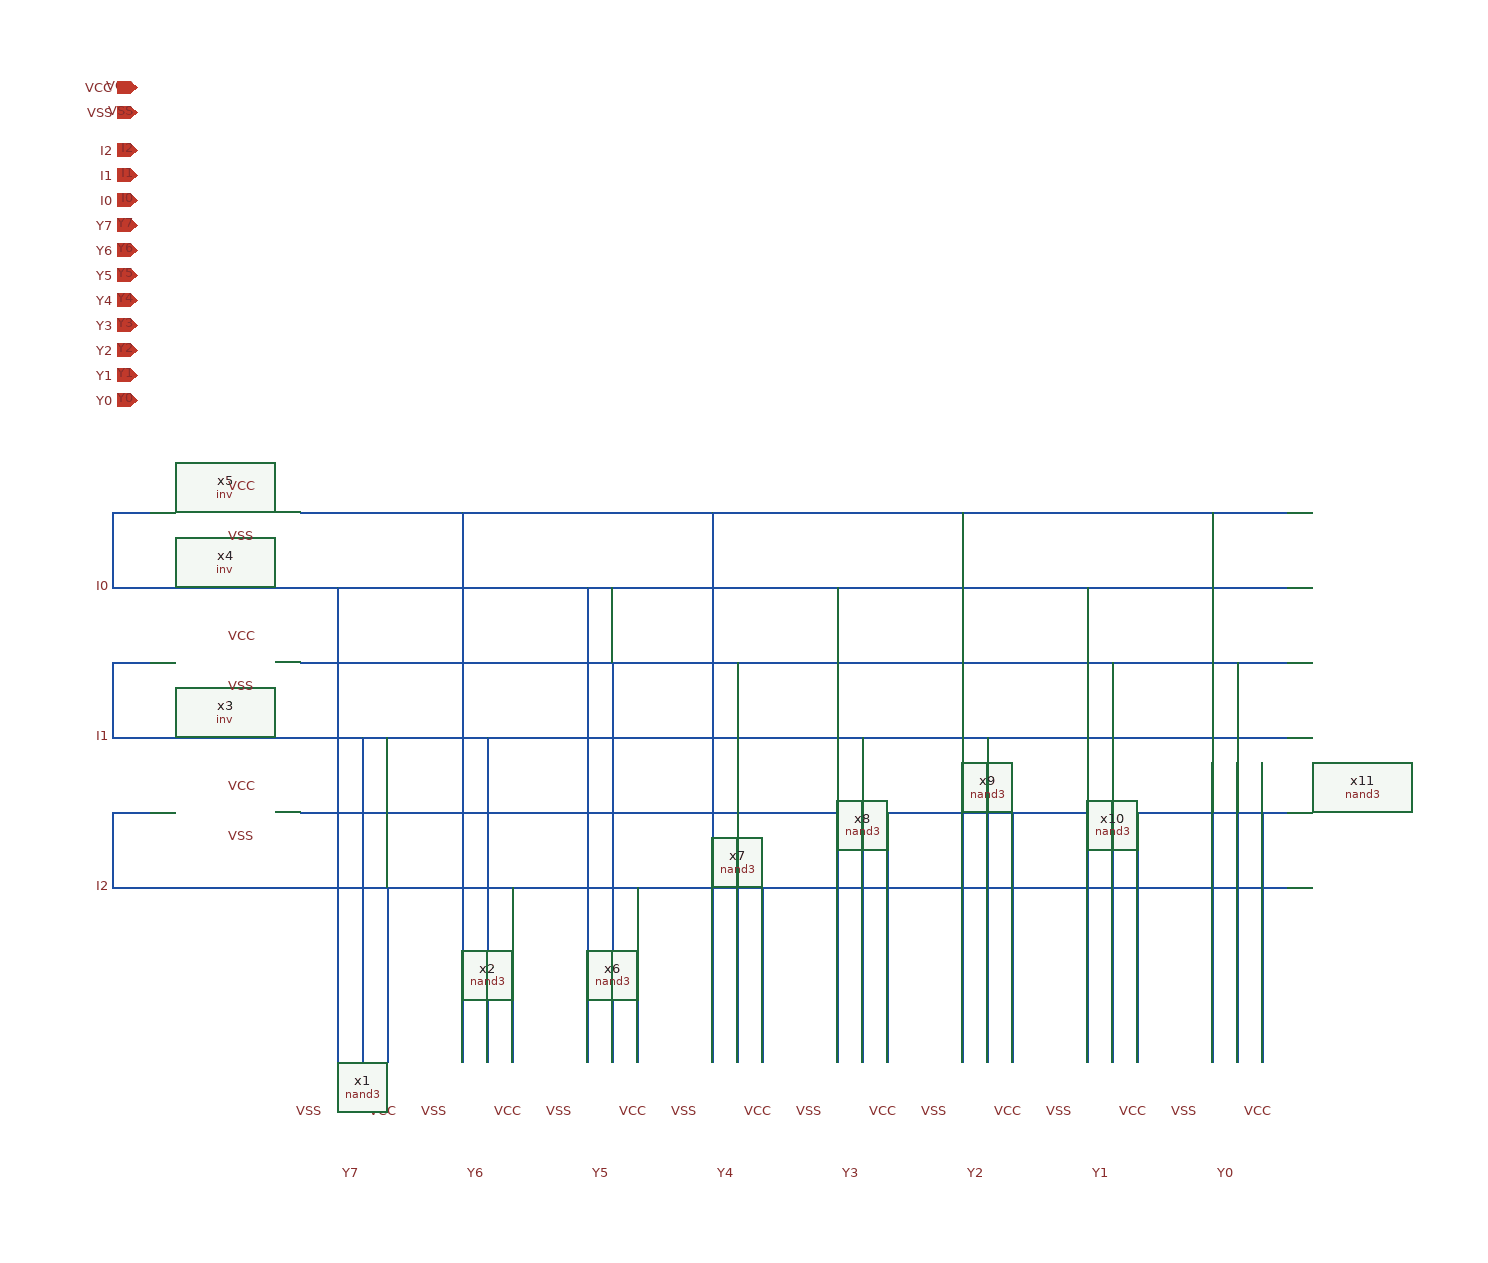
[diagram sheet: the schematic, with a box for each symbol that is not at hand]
v {xschem version=3.4.8RC file_version=1.3}
G {}
K {}
V {}
S {}
F {}
E {}
N 40 -240 40 -180 {lab=I0}
N 40 -240 70 -240 {lab=I0}
N 40 -120 40 -60 {lab=I1}
N 40 -120 70 -120 {lab=I1}
N 40 0 40 60 {lab=I2}
N 40 0 70 0 {lab=I2}
N 40 -180 980 -180 {lab=I0}
N 190 -240 980 -240 {lab=#net1}
N 40 -60 980 -60 {lab=I1}
N 190 -120 980 -120 {lab=#net2}
N 40 60 980 60 {lab=I2}
N 190 0 980 0 {lab=#net3}
N 220 -180 220 200 {lab=I0}
N 240 -60 240 200 {lab=I1}
N 260 60 260 200 {lab=I2}
N 360 60 360 200 {lab=I2}
N 460 60 460 200 {lab=I2}
N 560 60 560 200 {lab=I2}
N 660 0 660 200 {lab=#net3}
N 760 0 760 200 {lab=#net3}
N 860 0 860 200 {lab=#net3}
N 960 0 960 200 {lab=#net3}
N 320 -240 320 200 {lab=#net1}
N 520 -240 520 200 {lab=#net1}
N 720 -240 720 200 {lab=#net1}
N 920 -240 920 200 {lab=#net1}
N 420 -180 420 200 {lab=I0}
N 620 -180 620 200 {lab=I0}
N 820 -180 820 200 {lab=I0}
N 340 -60 340 200 {lab=I1}
N 440 -120 440 200 {lab=#net2}
N 540 -120 540 200 {lab=#net2}
N 640 -60 640 200 {lab=I1}
N 740 -60 740 200 {lab=I1}
N 840 -120 840 200 {lab=#net2}
N 940 -120 940 200 {lab=#net2}
C {iopin.sym} 60 -530 0 0 {name=p1 lab=I2}
C {iopin.sym} 60 -510 0 0 {name=p2 lab=I1}
C {iopin.sym} 60 -490 0 0 {name=p3 lab=I0}
C {iopin.sym} 60 -470 0 0 {name=p4 lab=Y7}
C {iopin.sym} 60 -450 0 0 {name=p5 lab=Y6}
C {iopin.sym} 60 -430 0 0 {name=p6 lab=Y5}
C {iopin.sym} 60 -410 0 0 {name=p7 lab=Y4}
C {iopin.sym} 60 -390 0 0 {name=p8 lab=Y3}
C {iopin.sym} 60 -370 0 0 {name=p9 lab=Y2}
C {iopin.sym} 60 -350 0 0 {name=p10 lab=Y1}
C {iopin.sym} 60 -330 0 0 {name=p11 lab=Y0}
C {inv.sym} 130 0 0 0 {name=x3}
C {lab_pin.sym} 60 -530 0 0 {name=p13 sig_type=std_logic lab=I2}
C {lab_pin.sym} 60 -510 0 0 {name=p14 sig_type=std_logic lab=I1}
C {lab_pin.sym} 60 -490 0 0 {name=p15 sig_type=std_logic lab=I0}
C {lab_pin.sym} 60 -470 0 0 {name=p12 sig_type=std_logic lab=Y7}
C {lab_pin.sym} 60 -450 0 0 {name=p16 sig_type=std_logic lab=Y6}
C {lab_pin.sym} 60 -430 0 0 {name=p17 sig_type=std_logic lab=Y5}
C {lab_pin.sym} 60 -410 0 0 {name=p18 sig_type=std_logic lab=Y4}
C {lab_pin.sym} 60 -390 0 0 {name=p19 sig_type=std_logic lab=Y3}
C {lab_pin.sym} 60 -370 0 0 {name=p20 sig_type=std_logic lab=Y2}
C {lab_pin.sym} 60 -350 0 0 {name=p21 sig_type=std_logic lab=Y1}
C {lab_pin.sym} 60 -330 0 0 {name=p22 sig_type=std_logic lab=Y0}
C {lab_pin.sym} 40 60 2 1 {name=p23 sig_type=std_logic lab=I2}
C {lab_pin.sym} 40 -60 2 1 {name=p24 sig_type=std_logic lab=I1}
C {lab_pin.sym} 40 -180 2 1 {name=p25 sig_type=std_logic lab=I0}
C {inv.sym} 130 -120 0 0 {name=x4}
C {inv.sym} 130 -240 0 0 {name=x5}
C {lab_pin.sym} 240 290 0 0 {name=p26 sig_type=std_logic lab=Y7}
C {lab_pin.sym} 340 290 0 0 {name=p27 sig_type=std_logic lab=Y6}
C {lab_pin.sym} 440 290 0 0 {name=p28 sig_type=std_logic lab=Y5}
C {lab_pin.sym} 540 290 0 0 {name=p29 sig_type=std_logic lab=Y4}
C {lab_pin.sym} 640 290 0 0 {name=p30 sig_type=std_logic lab=Y3}
C {lab_pin.sym} 740 290 0 0 {name=p31 sig_type=std_logic lab=Y2}
C {lab_pin.sym} 840 290 0 0 {name=p32 sig_type=std_logic lab=Y1}
C {lab_pin.sym} 940 290 0 0 {name=p33 sig_type=std_logic lab=Y0}
C {lab_pin.sym} 60 -580 0 0 {name=p34 sig_type=std_logic lab=VCC}
C {iopin.sym} 60 -580 0 0 {name=p35 lab=VCC}
C {iopin.sym} 60 -560 0 0 {name=p36 lab=VSS}
C {lab_pin.sym} 60 -560 0 0 {name=p37 sig_type=std_logic lab=VSS}
C {lab_pin.sym} 130 -260 0 1 {name=p38 sig_type=std_logic lab=VCC}
C {lab_pin.sym} 130 -220 0 1 {name=p39 sig_type=std_logic lab=VSS}
C {lab_pin.sym} 130 -140 0 1 {name=p40 sig_type=std_logic lab=VCC}
C {lab_pin.sym} 130 -100 0 1 {name=p41 sig_type=std_logic lab=VSS}
C {lab_pin.sym} 130 -20 0 1 {name=p42 sig_type=std_logic lab=VCC}
C {lab_pin.sym} 130 20 0 1 {name=p43 sig_type=std_logic lab=VSS}
C {lab_pin.sym} 970 240 1 0 {name=p44 sig_type=std_logic lab=VCC}
C {lab_pin.sym} 910 240 1 0 {name=p45 sig_type=std_logic lab=VSS}
C {lab_pin.sym} 870 240 1 0 {name=p46 sig_type=std_logic lab=VCC}
C {lab_pin.sym} 810 240 1 0 {name=p47 sig_type=std_logic lab=VSS}
C {lab_pin.sym} 770 240 1 0 {name=p48 sig_type=std_logic lab=VCC}
C {lab_pin.sym} 710 240 1 0 {name=p49 sig_type=std_logic lab=VSS}
C {lab_pin.sym} 670 240 1 0 {name=p50 sig_type=std_logic lab=VCC}
C {lab_pin.sym} 610 240 1 0 {name=p51 sig_type=std_logic lab=VSS}
C {lab_pin.sym} 570 240 1 0 {name=p52 sig_type=std_logic lab=VCC}
C {lab_pin.sym} 510 240 1 0 {name=p53 sig_type=std_logic lab=VSS}
C {lab_pin.sym} 470 240 1 0 {name=p54 sig_type=std_logic lab=VCC}
C {lab_pin.sym} 410 240 1 0 {name=p55 sig_type=std_logic lab=VSS}
C {lab_pin.sym} 370 240 1 0 {name=p56 sig_type=std_logic lab=VCC}
C {lab_pin.sym} 310 240 1 0 {name=p57 sig_type=std_logic lab=VSS}
C {lab_pin.sym} 270 240 1 0 {name=p58 sig_type=std_logic lab=VCC}
C {lab_pin.sym} 210 240 1 0 {name=p59 sig_type=std_logic lab=VSS}
C {logic gates/nand3.sym} 240 240 1 0 {name=x1}
C {logic gates/nand3.sym} 340 240 1 0 {name=x2}
C {logic gates/nand3.sym} 440 240 1 0 {name=x6}
C {logic gates/nand3.sym} 540 240 1 0 {name=x7}
C {logic gates/nand3.sym} 640 240 1 0 {name=x8}
C {logic gates/nand3.sym} 740 240 1 0 {name=x9}
C {logic gates/nand3.sym} 840 240 1 0 {name=x10}
C {logic gates/nand3.sym} 940 240 1 0 {name=x11}
